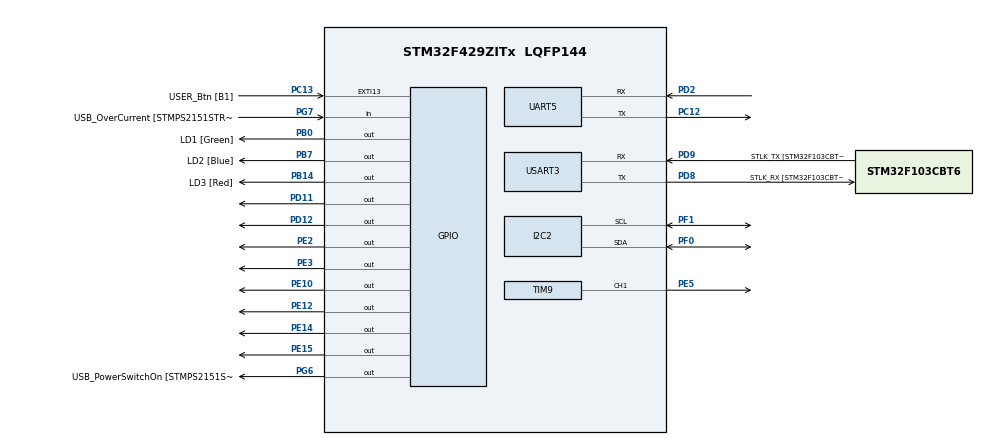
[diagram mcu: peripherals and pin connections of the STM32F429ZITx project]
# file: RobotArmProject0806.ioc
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Mcu.Family=STM32F4
Mcu.Name=STM32F429ZITx
Mcu.Package=LQFP144
NVIC.PriorityGroup=NVIC_PRIORITYGROUP_4
NVIC.TIM1_BRK_TIM9_IRQn=true\:0\:0\:false\:false\:true\:true\:true\:true
PA1.GPIO_Label=RMII_REF_CLK [LAN8742A-CZ-TR_REFCLK0]
PA1.Signal=ETH_REF_CLK
PA10.GPIO_Label=USB_ID
PA10.Signal=USB_OTG_FS_ID
PA11.GPIO_Label=USB_DM
PA11.Signal=USB_OTG_FS_DM
PA12.GPIO_Label=USB_DP
PA12.Signal=USB_OTG_FS_DP
PA13.GPIO_Label=TMS
PA13.Mode=Serial_Wire
PA13.Signal=SYS_JTMS-SWDIO
PA14.GPIO_Label=TCK
PA14.Mode=Serial_Wire
PA14.Signal=SYS_JTCK-SWCLK
PA2.GPIO_Label=RMII_MDIO [LAN8742A-CZ-TR_MDIO]
PA2.Signal=ETH_MDIO
PA7.GPIO_Label=RMII_CRS_DV [LAN8742A-CZ-TR_CRS_DV]
PA7.Signal=ETH_CRS_DV
PA8.GPIO_Label=USB_SOF [TP1]
PA8.Signal=USB_OTG_FS_SOF
PA9.GPIO_Label=USB_VBUS
PA9.Signal=USB_OTG_FS_VBUS
PB0.GPIO_Label=LD1 [Green]
PB0.Signal=GPIO_Output
PB13.GPIO_Label=RMII_TXD1 [LAN8742A-CZ-TR_TXD1]
PB13.Signal=ETH_TXD1
PB14.GPIO_Label=LD3 [Red]
PB14.Signal=GPIO_Output
PB7.GPIO_Label=LD2 [Blue]
PB7.Signal=GPIO_Output
PC1.GPIO_Label=RMII_MDC [LAN8742A-CZ-TR_MDC]
PC1.Signal=ETH_MDC
PC12.Mode=Asynchronous
PC12.Signal=UART5_TX
PC13.GPIO_Label=USER_Btn [B1]
PC13.Signal=GPXTI13
PC14/OSC32_IN.Mode=LSE-External-Oscillator
PC14/OSC32_IN.Signal=RCC_OSC32_IN
PC15/OSC32_OUT.Mode=LSE-External-Oscillator
PC15/OSC32_OUT.Signal=RCC_OSC32_OUT
PC4.GPIO_Label=RMII_RXD0 [LAN8742A-CZ-TR_RXD0]
PC4.Signal=ETH_RXD0
PC5.GPIO_Label=RMII_RXD1 [LAN8742A-CZ-TR_RXD1]
PC5.Signal=ETH_RXD1
PD11.Signal=GPIO_Output
PD12.Signal=GPIO_Output
PD2.Mode=Asynchronous
PD2.Signal=UART5_RX
PD8.GPIO_Label=STLK_RX [STM32F103CBT6_PA3]
PD8.Mode=Asynchronous
PD8.Signal=USART3_TX
PD9.GPIO_Label=STLK_TX [STM32F103CBT6_PA2]
PD9.Mode=Asynchronous
PD9.Signal=USART3_RX
PE10.Signal=GPIO_Output
PE12.Signal=GPIO_Output
PE14.Signal=GPIO_Output
PE15.Signal=GPIO_Output
PE2.Signal=GPIO_Output
PE3.Signal=GPIO_Output
PE5.Signal=S_TIM9_CH1
PF0.Mode=I2C
PF0.Signal=I2C2_SDA
PF1.Mode=I2C
PF1.Signal=I2C2_SCL
PG11.GPIO_Label=RMII_TX_EN [LAN8742A-CZ-TR_TXEN]
PG11.Signal=ETH_TX_EN
PG13.GPIO_Label=RMII_TXD0 [LAN8742A-CZ-TR_TXD0]
PG13.Signal=ETH_TXD0
PG6.GPIO_Label=USB_PowerSwitchOn [STMPS2151STR_EN]
PG6.Signal=GPIO_Output
PG7.GPIO_Label=USB_OverCurrent [STMPS2151STR_FAULT]
PG7.Signal=GPIO_Input
PH0/OSC_IN.GPIO_Label=MCO [STM32F103CBT6_PA8]
PH0/OSC_IN.Signal=RCC_OSC_IN
ProjectManager.HeapSize=0x200
ProjectManager.StackSize=0x400
ProjectManager.TargetToolchain=MDK-ARM V5.32
RCC.48MHZClocksFreq_Value=24000000
RCC.AHBFreq_Value=84000000
RCC.APB1CLKDivider=RCC_HCLK_DIV2
RCC.APB1Freq_Value=42000000
RCC.APB1TimFreq_Value=84000000
RCC.APB2CLKDivider=RCC_HCLK_DIV2
RCC.APB2Freq_Value=42000000
RCC.APB2TimFreq_Value=84000000
RCC.CortexFreq_Value=84000000
RCC.HCLKFreq_Value=84000000
RCC.HSE_VALUE=8000000
RCC.HSI_VALUE=16000000
RCC.PLLM=8
RCC.PLLMUL=RCC_PLL_MUL9
RCC.PLLN=84
RCC.PLLQ=7
RCC.PRESCALERUSB=RCC_USBCLKSOURCE_PLL_DIV1_5
RCC.SYSCLKFreq_VALUE=84000000
RCC.SYSCLKSource=RCC_SYSCLKSOURCE_PLLCLK
RCC.SYSCLKSourceVirtual=RCC_SYSCLKSOURCE_PLLCLK
RCC.USBFreq_Value=48000000
RCC.VCOOutputFreq_Value=168000000
SH.S_TIM9_CH1.0=TIM9_CH1,PWM Generation1 CH1
TIM9.Channel-PWM\ Generation1\ CH1=TIM_CHANNEL_1
TIM9.Period=10000-1
TIM9.Prescaler=84-1
TIM9.Pulse-PWM\ Generation1\ CH1=5000
UART5.VirtualMode=Asynchronous
USART3.VirtualMode=VM_ASYNC
VP_RTC_VS_RTC_Activate.Mode=RTC_Enabled
VP_TIM9_VS_ClockSourceINT.Mode=Internal
board=NUCLEO-F429ZI

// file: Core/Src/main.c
/* USER CODE BEGIN Header */
/**
  ******************************************************************************
  * @file           : main.c
  * @brief          : Main program body
  ******************************************************************************
  * @attention
  *
  * Copyright (c) 2022 STMicroelectronics.
  * All rights reserved.
  *
  * This software is licensed under terms that can be found in the LICENSE file
  * in the root directory of this software component.
  * If no LICENSE file comes with this software, it is provided AS-IS.
  *
  ******************************************************************************
  */
/* USER CODE END Header */
#include "main.h"

/* USER CODE BEGIN Includes */
#include "pca9685.h"

/* USER CODE END Includes */

I2C_HandleTypeDef hi2c2;

RTC_HandleTypeDef hrtc;

TIM_HandleTypeDef htim9;

UART_HandleTypeDef huart5;
UART_HandleTypeDef huart3;

/* USER CODE BEGIN PV */
			#define DcMotor1Enable() HAL_GPIO_WritePin(GPIOE, GPIO_PIN_2,0)
      #define DcMotor1Disable() HAL_GPIO_WritePin(GPIOE, GPIO_PIN_2,1)
      #define DcMotor1DirCw() HAL_GPIO_WritePin(GPIOE, GPIO_PIN_3,0)
      #define DcMotor1DirCcw() HAL_GPIO_WritePin(GPIOE, GPIO_PIN_3,1)

			#define DcPIND_11ON() HAL_GPIO_WritePin(GPIOD, GPIO_PIN_11,1)
			#define DcPIND_11OFF() HAL_GPIO_WritePin(GPIOD, GPIO_PIN_11,0)
			#define DcPIND_12ON() HAL_GPIO_WritePin(GPIOD, GPIO_PIN_12,1)
			#define DcPIND_12OFF() HAL_GPIO_WritePin(GPIOD, GPIO_PIN_12,0)

			uint8_t ActiveServo;

/* USER CODE END PV */

void SystemClock_Config(void);
static void MX_GPIO_Init(void);
static void MX_I2C2_Init(void);
static void MX_RTC_Init(void);
static void MX_TIM9_Init(void);
static void MX_UART5_Init(void);
static void MX_USART3_UART_Init(void);

int main(void)
{

  /* MCU Configuration--------------------------------------------------------*/

  /* Reset of all peripherals, Initializes the Flash interface and the Systick. */
  HAL_Init();

  /* Configure the system clock */
  SystemClock_Config();

  /* Initialize all configured peripherals */
  MX_GPIO_Init();
  MX_I2C2_Init();
  MX_RTC_Init();
  MX_TIM9_Init();
  MX_UART5_Init();
  MX_USART3_UART_Init();
  /* USER CODE BEGIN 2 */
	uint8_t data;
	HAL_TIM_PWM_Start(&htim9, TIM_CHANNEL_1);
	PCA9685_Init(&hi2c2); //add 0723
	HAL_Delay(1000); // add 0723
	HAL_GPIO_WritePin (GPIOE, GPIO_PIN_10, GPIO_PIN_RESET);   // IN1 HIGH
  HAL_GPIO_WritePin (GPIOE, GPIO_PIN_12, GPIO_PIN_RESET);
  HAL_GPIO_WritePin (GPIOE, GPIO_PIN_14, GPIO_PIN_RESET);
  HAL_GPIO_WritePin (GPIOE, GPIO_PIN_15, GPIO_PIN_RESET);

  /* USER CODE END 2 */

  /* Infinite loop */
  /* USER CODE BEGIN WHILE */
  while (1)
  {
PCA9685_SetServoAngle(0, 30);
PCA9685_SetServoAngle(1, 15);
PCA9685_SetServoAngle(10, 0);
HAL_Delay (1500);
DcPIND_11OFF();
DcPIND_12ON();
HAL_Delay (3000);
DcPIND_11ON();
DcPIND_12ON();
for (int i=0; i<35; i++)   // for 360 deg rotation
   {
 HAL_GPIO_WritePin (GPIOE, GPIO_PIN_10, GPIO_PIN_SET);   // IN1 HIGH
 HAL_GPIO_WritePin (GPIOE, GPIO_PIN_12, GPIO_PIN_RESET);
 HAL_GPIO_WritePin (GPIOE, GPIO_PIN_14, GPIO_PIN_RESET);
 HAL_GPIO_WritePin (GPIOE, GPIO_PIN_15, GPIO_PIN_RESET);

 HAL_Delay (2);

 HAL_GPIO_WritePin (GPIOE, GPIO_PIN_10, GPIO_PIN_RESET);
 HAL_GPIO_WritePin (GPIOE, GPIO_PIN_12, GPIO_PIN_SET);   // IN2 HIGH
 HAL_GPIO_WritePin (GPIOE, GPIO_PIN_14, GPIO_PIN_RESET);
 HAL_GPIO_WritePin (GPIOE, GPIO_PIN_15, GPIO_PIN_RESET);

 HAL_Delay (2);

 HAL_GPIO_WritePin (GPIOE, GPIO_PIN_10, GPIO_PIN_RESET);
 HAL_GPIO_WritePin (GPIOE, GPIO_PIN_12, GPIO_PIN_RESET);
 HAL_GPIO_WritePin (GPIOE, GPIO_PIN_14, GPIO_PIN_SET);   // IN3 HIGH
 HAL_GPIO_WritePin (GPIOE, GPIO_PIN_15, GPIO_PIN_RESET);

 HAL_Delay (2);

 HAL_GPIO_WritePin (GPIOE, GPIO_PIN_10, GPIO_PIN_RESET);
 HAL_GPIO_WritePin (GPIOE, GPIO_PIN_12, GPIO_PIN_RESET);
 HAL_GPIO_WritePin (GPIOE, GPIO_PIN_14, GPIO_PIN_RESET);
 HAL_GPIO_WritePin (GPIOE, GPIO_PIN_15, GPIO_PIN_SET);    // IN4 HIGH

 HAL_Delay (2);
 }
HAL_Delay(2000);
for (int i=0; i<35; i++)   // for 360 deg rotation
   {
 HAL_GPIO_WritePin (GPIOE, GPIO_PIN_10, GPIO_PIN_RESET);   // IN1 HIGH
 HAL_GPIO_WritePin (GPIOE, GPIO_PIN_12, GPIO_PIN_RESET);
 HAL_GPIO_WritePin (GPIOE, GPIO_PIN_14, GPIO_PIN_RESET);
 HAL_GPIO_WritePin (GPIOE, GPIO_PIN_15, GPIO_PIN_SET);

 HAL_Delay (2);

 HAL_GPIO_WritePin (GPIOE, GPIO_PIN_10, GPIO_PIN_RESET);
 HAL_GPIO_WritePin (GPIOE, GPIO_PIN_12, GPIO_PIN_RESET);   // IN2 HIGH
 HAL_GPIO_WritePin (GPIOE, GPIO_PIN_14, GPIO_PIN_SET);
 HAL_GPIO_WritePin (GPIOE, GPIO_PIN_15, GPIO_PIN_RESET);

 HAL_Delay (2);

 HAL_GPIO_WritePin (GPIOE, GPIO_PIN_10, GPIO_PIN_RESET);
 HAL_GPIO_WritePin (GPIOE, GPIO_PIN_12, GPIO_PIN_SET);
 HAL_GPIO_WritePin (GPIOE, GPIO_PIN_14, GPIO_PIN_RESET);   // IN3 HIGH
 HAL_GPIO_WritePin (GPIOE, GPIO_PIN_15, GPIO_PIN_RESET);

 HAL_Delay (2);

 HAL_GPIO_WritePin (GPIOE, GPIO_PIN_10, GPIO_PIN_SET);
 HAL_GPIO_WritePin (GPIOE, GPIO_PIN_12, GPIO_PIN_RESET);
 HAL_GPIO_WritePin (GPIOE, GPIO_PIN_14, GPIO_PIN_RESET);
 HAL_GPIO_WritePin (GPIOE, GPIO_PIN_15, GPIO_PIN_RESET);    // IN4 HIGH

 HAL_Delay (2);
 }
HAL_Delay(2000);
PCA9685_SetServoAngle(1, 115);
HAL_Delay(2000);
PCA9685_SetServoAngle(0, 10);
HAL_Delay(2000);
PCA9685_SetServoAngle(1, 157);
HAL_Delay(2000);
PCA9685_SetServoAngle(1, 115);
HAL_Delay(2000);
PCA9685_SetServoAngle(1, 65);
HAL_Delay(2000);
PCA9685_SetServoAngle(10, 65);
HAL_Delay(2000);
PCA9685_SetServoAngle(1, 105);
HAL_Delay(2000);
PCA9685_SetServoAngle(0, 55);
HAL_Delay(2000);
PCA9685_SetServoAngle(1, 115);
HAL_Delay(2000);

TIM9->CCR1 = 2900;
		  PCA9685_SetServoAngle(1, 120);
			HAL_Delay(500);
			HAL_GPIO_WritePin(GPIOE,GPIO_PIN_2,0); // AIN -> 0 // dc sipza driver
      HAL_GPIO_WritePin(GPIOE,GPIO_PIN_3,1);
	    HAL_Delay(500);
	    PCA9685_SetServoAngle(1, 122);
			HAL_Delay(500);
			HAL_GPIO_WritePin(GPIOE,GPIO_PIN_2,0); // AIN -> 0 // dc sipza driver
      HAL_GPIO_WritePin(GPIOE,GPIO_PIN_3,1);
	    HAL_Delay(500);
	    PCA9685_SetServoAngle(1, 124);
			HAL_Delay(500);
			HAL_GPIO_WritePin(GPIOE,GPIO_PIN_2,0); // AIN -> 0 // dc sipza driver
      HAL_GPIO_WritePin(GPIOE,GPIO_PIN_3,1);
	    HAL_Delay(500);
			PCA9685_SetServoAngle(1, 126);
			HAL_Delay(500);
			HAL_GPIO_WritePin(GPIOE,GPIO_PIN_2,0); // AIN -> 0 // dc sipza driver
      HAL_GPIO_WritePin(GPIOE,GPIO_PIN_3,1);
	    HAL_Delay(500);
			PCA9685_SetServoAngle(1, 128);
			HAL_Delay(500);
			HAL_GPIO_WritePin(GPIOE,GPIO_PIN_2,0); // AIN -> 0 // dc sipza driver
      HAL_GPIO_WritePin(GPIOE,GPIO_PIN_3,1);
	    HAL_Delay(500);
			HAL_GPIO_WritePin(GPIOE,GPIO_PIN_2,1); // AIN -> 0 // dc sipza driver
      HAL_GPIO_WritePin(GPIOE,GPIO_PIN_3,1);
			HAL_Delay(2000);
	    PCA9685_SetServoAngle(1, 130);
			HAL_Delay(500);
			HAL_GPIO_WritePin(GPIOE,GPIO_PIN_2,0); // AIN -> 0 // dc sipza driver
      HAL_GPIO_WritePin(GPIOE,GPIO_PIN_3,1);
	    HAL_Delay(500);
			HAL_GPIO_WritePin(GPIOE,GPIO_PIN_2,1); // AIN -> 0 // dc sipza driver
      HAL_GPIO_WritePin(GPIOE,GPIO_PIN_3,1);
	    HAL_Delay(500);

PCA9685_SetServoAngle(1, 65);
HAL_Delay(2000);
PCA9685_SetServoAngle(0, 30);
PCA9685_SetServoAngle(1, 15);
PCA9685_SetServoAngle(10, 0);
HAL_Delay(3000);
DcPIND_11ON();
DcPIND_12OFF();
HAL_Delay(3000);
DcPIND_11ON();
DcPIND_12ON();
break;
}
  /* USER CODE END 3 */
}

void SystemClock_Config(void)
{
  RCC_OscInitTypeDef RCC_OscInitStruct = {0};
  RCC_ClkInitTypeDef RCC_ClkInitStruct = {0};

  /** Configure the main internal regulator output voltage
  */
  __HAL_RCC_PWR_CLK_ENABLE();
  __HAL_PWR_VOLTAGESCALING_CONFIG(PWR_REGULATOR_VOLTAGE_SCALE1);

  /** Initializes the RCC Oscillators according to the specified parameters
  * in the RCC_OscInitTypeDef structure.
  */
  RCC_OscInitStruct.OscillatorType = RCC_OSCILLATORTYPE_HSI|RCC_OSCILLATORTYPE_LSI;
  RCC_OscInitStruct.HSIState = RCC_HSI_ON;
  RCC_OscInitStruct.HSICalibrationValue = RCC_HSICALIBRATION_DEFAULT;
  RCC_OscInitStruct.LSIState = RCC_LSI_ON;
  RCC_OscInitStruct.PLL.PLLState = RCC_PLL_ON;
  RCC_OscInitStruct.PLL.PLLSource = RCC_PLLSOURCE_HSI;
  RCC_OscInitStruct.PLL.PLLM = 8;
  RCC_OscInitStruct.PLL.PLLN = 180;
  RCC_OscInitStruct.PLL.PLLP = RCC_PLLP_DIV2;
  RCC_OscInitStruct.PLL.PLLQ = 7;
  if (HAL_RCC_OscConfig(&RCC_OscInitStruct) != HAL_OK)
  {
    Error_Handler();
  }

  /** Activate the Over-Drive mode
  */
  if (HAL_PWREx_EnableOverDrive() != HAL_OK)
  {
    Error_Handler();
  }

  /** Initializes the CPU, AHB and APB buses clocks
  */
  RCC_ClkInitStruct.ClockType = RCC_CLOCKTYPE_HCLK|RCC_CLOCKTYPE_SYSCLK
                              |RCC_CLOCKTYPE_PCLK1|RCC_CLOCKTYPE_PCLK2;
  RCC_ClkInitStruct.SYSCLKSource = RCC_SYSCLKSOURCE_PLLCLK;
  RCC_ClkInitStruct.AHBCLKDivider = RCC_SYSCLK_DIV1;
  RCC_ClkInitStruct.APB1CLKDivider = RCC_HCLK_DIV4;
  RCC_ClkInitStruct.APB2CLKDivider = RCC_HCLK_DIV2;

  if (HAL_RCC_ClockConfig(&RCC_ClkInitStruct, FLASH_LATENCY_5) != HAL_OK)
  {
    Error_Handler();
  }
}

static void MX_I2C2_Init(void)
{

  hi2c2.Instance = I2C2;
  hi2c2.Init.ClockSpeed = 100000;
  hi2c2.Init.DutyCycle = I2C_DUTYCYCLE_2;
  hi2c2.Init.OwnAddress1 = 0;
  hi2c2.Init.AddressingMode = I2C_ADDRESSINGMODE_7BIT;
  hi2c2.Init.DualAddressMode = I2C_DUALADDRESS_DISABLE;
  hi2c2.Init.OwnAddress2 = 0;
  hi2c2.Init.GeneralCallMode = I2C_GENERALCALL_DISABLE;
  hi2c2.Init.NoStretchMode = I2C_NOSTRETCH_DISABLE;
  if (HAL_I2C_Init(&hi2c2) != HAL_OK)
  {
    Error_Handler();
  }

  /** Configure Analogue filter
  */
  if (HAL_I2CEx_ConfigAnalogFilter(&hi2c2, I2C_ANALOGFILTER_ENABLE) != HAL_OK)
  {
    Error_Handler();
  }

  /** Configure Digital filter
  */
  if (HAL_I2CEx_ConfigDigitalFilter(&hi2c2, 0) != HAL_OK)
  {
    Error_Handler();
  }

}

static void MX_RTC_Init(void)
{

  /** Initialize RTC Only
  */
  hrtc.Instance = RTC;
  hrtc.Init.HourFormat = RTC_HOURFORMAT_24;
  hrtc.Init.AsynchPrediv = 127;
  hrtc.Init.SynchPrediv = 255;
  hrtc.Init.OutPut = RTC_OUTPUT_DISABLE;
  hrtc.Init.OutPutPolarity = RTC_OUTPUT_POLARITY_HIGH;
  hrtc.Init.OutPutType = RTC_OUTPUT_TYPE_OPENDRAIN;
  if (HAL_RTC_Init(&hrtc) != HAL_OK)
  {
    Error_Handler();
  }

}

static void MX_TIM9_Init(void)
{

  TIM_ClockConfigTypeDef sClockSourceConfig = {0};
  TIM_OC_InitTypeDef sConfigOC = {0};

  htim9.Instance = TIM9;
  htim9.Init.Prescaler = 84-1;
  htim9.Init.CounterMode = TIM_COUNTERMODE_UP;
  htim9.Init.Period = 10000-1;
  htim9.Init.ClockDivision = TIM_CLOCKDIVISION_DIV1;
  htim9.Init.AutoReloadPreload = TIM_AUTORELOAD_PRELOAD_DISABLE;
  if (HAL_TIM_Base_Init(&htim9) != HAL_OK)
  {
    Error_Handler();
  }
  sClockSourceConfig.ClockSource = TIM_CLOCKSOURCE_INTERNAL;
  if (HAL_TIM_ConfigClockSource(&htim9, &sClockSourceConfig) != HAL_OK)
  {
    Error_Handler();
  }
  if (HAL_TIM_PWM_Init(&htim9) != HAL_OK)
  {
    Error_Handler();
  }
  sConfigOC.OCMode = TIM_OCMODE_PWM1;
  sConfigOC.Pulse = 5000;
  sConfigOC.OCPolarity = TIM_OCPOLARITY_HIGH;
  sConfigOC.OCFastMode = TIM_OCFAST_DISABLE;
  if (HAL_TIM_PWM_ConfigChannel(&htim9, &sConfigOC, TIM_CHANNEL_1) != HAL_OK)
  {
    Error_Handler();
  }
  HAL_TIM_MspPostInit(&htim9);

}

static void MX_UART5_Init(void)
{

  huart5.Instance = UART5;
  huart5.Init.BaudRate = 115200;
  huart5.Init.WordLength = UART_WORDLENGTH_8B;
  huart5.Init.StopBits = UART_STOPBITS_1;
  huart5.Init.Parity = UART_PARITY_NONE;
  huart5.Init.Mode = UART_MODE_TX_RX;
  huart5.Init.HwFlowCtl = UART_HWCONTROL_NONE;
  huart5.Init.OverSampling = UART_OVERSAMPLING_16;
  if (HAL_UART_Init(&huart5) != HAL_OK)
  {
    Error_Handler();
  }

}

static void MX_USART3_UART_Init(void)
{

  huart3.Instance = USART3;
  huart3.Init.BaudRate = 115200;
  huart3.Init.WordLength = UART_WORDLENGTH_8B;
  huart3.Init.StopBits = UART_STOPBITS_1;
  huart3.Init.Parity = UART_PARITY_NONE;
  huart3.Init.Mode = UART_MODE_TX_RX;
  huart3.Init.HwFlowCtl = UART_HWCONTROL_NONE;
  huart3.Init.OverSampling = UART_OVERSAMPLING_16;
  if (HAL_UART_Init(&huart3) != HAL_OK)
  {
    Error_Handler();
  }

}

static void MX_GPIO_Init(void)
{
  GPIO_InitTypeDef GPIO_InitStruct = {0};

  /* GPIO Ports Clock Enable */
  __HAL_RCC_GPIOE_CLK_ENABLE();
  __HAL_RCC_GPIOC_CLK_ENABLE();
  __HAL_RCC_GPIOF_CLK_ENABLE();
  __HAL_RCC_GPIOH_CLK_ENABLE();
  __HAL_RCC_GPIOA_CLK_ENABLE();
  __HAL_RCC_GPIOB_CLK_ENABLE();
  __HAL_RCC_GPIOD_CLK_ENABLE();
  __HAL_RCC_GPIOG_CLK_ENABLE();

  /*Configure GPIO pin Output Level */
  HAL_GPIO_WritePin(GPIOE, GPIO_PIN_2|GPIO_PIN_3|GPIO_PIN_10|GPIO_PIN_12
                          |GPIO_PIN_14|GPIO_PIN_15, GPIO_PIN_RESET);

  /*Configure GPIO pin Output Level */
  HAL_GPIO_WritePin(GPIOB, LD1_Pin|LD3_Pin|LD2_Pin, GPIO_PIN_RESET);

  /*Configure GPIO pin Output Level */
  HAL_GPIO_WritePin(GPIOD, GPIO_PIN_11|GPIO_PIN_12, GPIO_PIN_RESET);

  /*Configure GPIO pin Output Level */
  HAL_GPIO_WritePin(USB_PowerSwitchOn_GPIO_Port, USB_PowerSwitchOn_Pin, GPIO_PIN_RESET);

  /*Configure GPIO pins : PE2 PE3 PE10 PE12
                           PE14 PE15 */
  GPIO_InitStruct.Pin = GPIO_PIN_2|GPIO_PIN_3|GPIO_PIN_10|GPIO_PIN_12
                          |GPIO_PIN_14|GPIO_PIN_15;
  GPIO_InitStruct.Mode = GPIO_MODE_OUTPUT_PP;
  GPIO_InitStruct.Pull = GPIO_NOPULL;
  GPIO_InitStruct.Speed = GPIO_SPEED_FREQ_LOW;
  HAL_GPIO_Init(GPIOE, &GPIO_InitStruct);

  /*Configure GPIO pin : USER_Btn_Pin */
  GPIO_InitStruct.Pin = USER_Btn_Pin;
  GPIO_InitStruct.Mode = GPIO_MODE_IT_RISING;
  GPIO_InitStruct.Pull = GPIO_NOPULL;
  HAL_GPIO_Init(USER_Btn_GPIO_Port, &GPIO_InitStruct);

  /*Configure GPIO pins : RMII_MDC_Pin RMII_RXD0_Pin RMII_RXD1_Pin */
  GPIO_InitStruct.Pin = RMII_MDC_Pin|RMII_RXD0_Pin|RMII_RXD1_Pin;
  GPIO_InitStruct.Mode = GPIO_MODE_AF_PP;
  GPIO_InitStruct.Pull = GPIO_NOPULL;
  GPIO_InitStruct.Speed = GPIO_SPEED_FREQ_VERY_HIGH;
  GPIO_InitStruct.Alternate = GPIO_AF11_ETH;
  HAL_GPIO_Init(GPIOC, &GPIO_InitStruct);

  /*Configure GPIO pins : RMII_REF_CLK_Pin RMII_MDIO_Pin RMII_CRS_DV_Pin */
  GPIO_InitStruct.Pin = RMII_REF_CLK_Pin|RMII_MDIO_Pin|RMII_CRS_DV_Pin;
  GPIO_InitStruct.Mode = GPIO_MODE_AF_PP;
  GPIO_InitStruct.Pull = GPIO_NOPULL;
  GPIO_InitStruct.Speed = GPIO_SPEED_FREQ_VERY_HIGH;
  GPIO_InitStruct.Alternate = GPIO_AF11_ETH;
  HAL_GPIO_Init(GPIOA, &GPIO_InitStruct);

  /*Configure GPIO pins : LD1_Pin LD3_Pin LD2_Pin */
  GPIO_InitStruct.Pin = LD1_Pin|LD3_Pin|LD2_Pin;
  GPIO_InitStruct.Mode = GPIO_MODE_OUTPUT_PP;
  GPIO_InitStruct.Pull = GPIO_NOPULL;
  GPIO_InitStruct.Speed = GPIO_SPEED_FREQ_LOW;
  HAL_GPIO_Init(GPIOB, &GPIO_InitStruct);

  /*Configure GPIO pin : RMII_TXD1_Pin */
  GPIO_InitStruct.Pin = RMII_TXD1_Pin;
  GPIO_InitStruct.Mode = GPIO_MODE_AF_PP;
  GPIO_InitStruct.Pull = GPIO_NOPULL;
  GPIO_InitStruct.Speed = GPIO_SPEED_FREQ_VERY_HIGH;
  GPIO_InitStruct.Alternate = GPIO_AF11_ETH;
  HAL_GPIO_Init(RMII_TXD1_GPIO_Port, &GPIO_InitStruct);

  /*Configure GPIO pins : PD11 PD12 */
  GPIO_InitStruct.Pin = GPIO_PIN_11|GPIO_PIN_12;
  GPIO_InitStruct.Mode = GPIO_MODE_OUTPUT_PP;
  GPIO_InitStruct.Pull = GPIO_NOPULL;
  GPIO_InitStruct.Speed = GPIO_SPEED_FREQ_LOW;
  HAL_GPIO_Init(GPIOD, &GPIO_InitStruct);

  /*Configure GPIO pin : USB_PowerSwitchOn_Pin */
  GPIO_InitStruct.Pin = USB_PowerSwitchOn_Pin;
  GPIO_InitStruct.Mode = GPIO_MODE_OUTPUT_PP;
  GPIO_InitStruct.Pull = GPIO_NOPULL;
  GPIO_InitStruct.Speed = GPIO_SPEED_FREQ_LOW;
  HAL_GPIO_Init(USB_PowerSwitchOn_GPIO_Port, &GPIO_InitStruct);

  /*Configure GPIO pin : USB_OverCurrent_Pin */
  GPIO_InitStruct.Pin = USB_OverCurrent_Pin;
  GPIO_InitStruct.Mode = GPIO_MODE_INPUT;
  GPIO_InitStruct.Pull = GPIO_NOPULL;
  HAL_GPIO_Init(USB_OverCurrent_GPIO_Port, &GPIO_InitStruct);

  /*Configure GPIO pins : USB_SOF_Pin USB_ID_Pin USB_DM_Pin USB_DP_Pin */
  GPIO_InitStruct.Pin = USB_SOF_Pin|USB_ID_Pin|USB_DM_Pin|USB_DP_Pin;
  GPIO_InitStruct.Mode = GPIO_MODE_AF_PP;
  GPIO_InitStruct.Pull = GPIO_NOPULL;
  GPIO_InitStruct.Speed = GPIO_SPEED_FREQ_VERY_HIGH;
  GPIO_InitStruct.Alternate = GPIO_AF10_OTG_FS;
  HAL_GPIO_Init(GPIOA, &GPIO_InitStruct);

  /*Configure GPIO pin : USB_VBUS_Pin */
  GPIO_InitStruct.Pin = USB_VBUS_Pin;
  GPIO_InitStruct.Mode = GPIO_MODE_INPUT;
  GPIO_InitStruct.Pull = GPIO_NOPULL;
  HAL_GPIO_Init(USB_VBUS_GPIO_Port, &GPIO_InitStruct);

  /*Configure GPIO pins : RMII_TX_EN_Pin RMII_TXD0_Pin */
  GPIO_InitStruct.Pin = RMII_TX_EN_Pin|RMII_TXD0_Pin;
  GPIO_InitStruct.Mode = GPIO_MODE_AF_PP;
  GPIO_InitStruct.Pull = GPIO_NOPULL;
  GPIO_InitStruct.Speed = GPIO_SPEED_FREQ_VERY_HIGH;
  GPIO_InitStruct.Alternate = GPIO_AF11_ETH;
  HAL_GPIO_Init(GPIOG, &GPIO_InitStruct);

}

void Error_Handler(void)
{
  __disable_irq();
  while (1)
  {
  }
}
